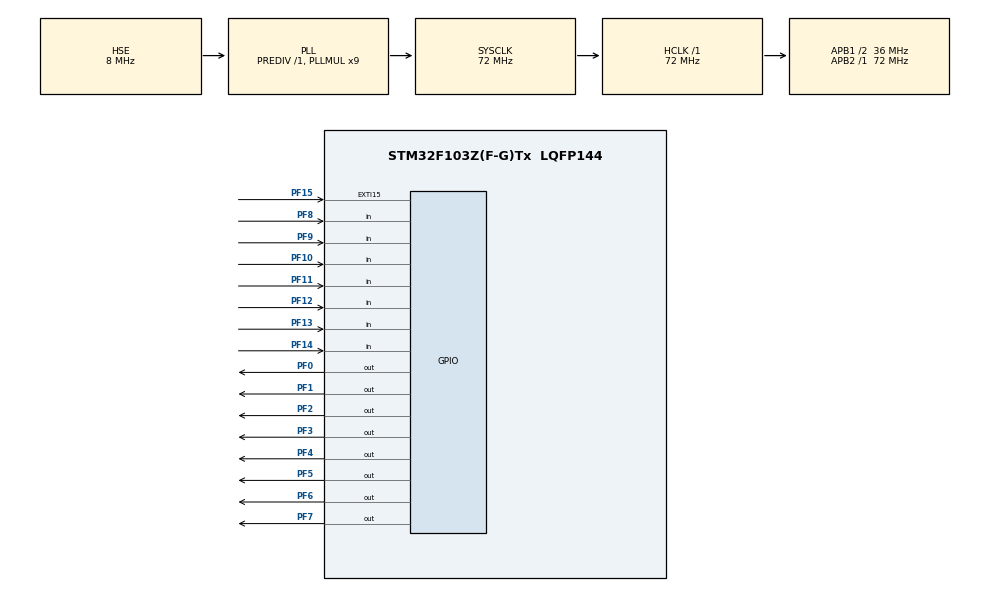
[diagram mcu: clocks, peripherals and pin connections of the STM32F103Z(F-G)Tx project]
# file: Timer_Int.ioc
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Mcu.Family=STM32F1
Mcu.Name=STM32F103Z(F-G)Tx
Mcu.Package=LQFP144
NVIC.EXTI15_10_IRQn=true\:0\:0\:false\:false\:true\:true\:true
NVIC.PriorityGroup=NVIC_PRIORITYGROUP_4
NVIC.TIM3_IRQn=true\:0\:0\:false\:false\:true\:true\:true
OSC_IN.Mode=HSE-External-Oscillator
OSC_IN.Signal=RCC_OSC_IN
OSC_OUT.Mode=HSE-External-Oscillator
OSC_OUT.Signal=RCC_OSC_OUT
PA13.Mode=Serial_Wire
PA13.Signal=SYS_JTMS-SWDIO
PA14.Mode=Serial_Wire
PA14.Signal=SYS_JTCK-SWCLK
PF0.Signal=GPIO_Output
PF1.Signal=GPIO_Output
PF10.Signal=GPIO_Input
PF11.Signal=GPIO_Input
PF12.Signal=GPIO_Input
PF13.Signal=GPIO_Input
PF14.Signal=GPIO_Input
PF15.GPIO_ModeDefaultEXTI=GPIO_MODE_IT_RISING
PF15.Signal=GPXTI15
PF2.Signal=GPIO_Output
PF3.Signal=GPIO_Output
PF4.Signal=GPIO_Output
PF5.Signal=GPIO_Output
PF6.Signal=GPIO_Output
PF7.Signal=GPIO_Output
PF8.Signal=GPIO_Input
PF9.Signal=GPIO_Input
ProjectManager.HeapSize=0x200
ProjectManager.StackSize=0x400
ProjectManager.TargetToolchain=MDK-ARM V5.27
RCC.AHBFreq_Value=72000000
RCC.APB1CLKDivider=RCC_HCLK_DIV2
RCC.APB1Freq_Value=36000000
RCC.APB1TimFreq_Value=72000000
RCC.APB2Freq_Value=72000000
RCC.APB2TimFreq_Value=72000000
RCC.HCLKFreq_Value=72000000
RCC.PLLMUL=RCC_PLL_MUL9
RCC.PLLSourceVirtual=RCC_PLLSOURCE_HSE
RCC.SYSCLKFreq_VALUE=72000000
RCC.SYSCLKSource=RCC_SYSCLKSOURCE_PLLCLK
RCC.USBFreq_Value=72000000
TIM3.AutoReloadPreload=TIM_AUTORELOAD_PRELOAD_DISABLE
VP_TIM3_VS_ClockSourceINT.Mode=Internal
board=custom

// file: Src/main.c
/* USER CODE BEGIN Header */
/**
  ******************************************************************************
  * @file           : main.c
  * @brief          : Main program body
  ******************************************************************************
  * @attention
  *
  * <h2><center>&copy; Copyright (c) 2021 STMicroelectronics.
  * All rights reserved.</center></h2>
  *
  * This software component is licensed by ST under BSD 3-Clause license,
  * the "License"; You may not use this file except in compliance with the
  * License. You may obtain a copy of the License at:
  *                        opensource.org/licenses/BSD-3-Clause
  *
  ******************************************************************************
  */
/* USER CODE END Header */
#include "main.h"

TIM_HandleTypeDef htim3;

void SystemClock_Config(void);
static void MX_GPIO_Init(void);
static void MX_TIM3_Init(void);

int main(void)
{

  HAL_Init();

  /* Configure the system clock */
  SystemClock_Config();

  /* Initialize all configured peripherals */
  MX_GPIO_Init();
  MX_TIM3_Init();
  /* USER CODE BEGIN 2 */

  HAL_GPIO_WritePin(GPIOA, GPIO_PIN_0, GPIO_PIN_RESET);
	HAL_GPIO_WritePin(GPIOA, GPIO_PIN_1, GPIO_PIN_RESET);
	HAL_GPIO_WritePin(GPIOA, GPIO_PIN_2, GPIO_PIN_RESET);

	HAL_GPIO_WritePin(GPIOF, GPIO_PIN_1, GPIO_PIN_SET);

	HAL_TIM_Base_Start_IT(&htim3);

  while (1)
  {
       //HAL_Delay(1000);
  }

}

void SystemClock_Config(void)
{
  RCC_OscInitTypeDef RCC_OscInitStruct = {0};
  RCC_ClkInitTypeDef RCC_ClkInitStruct = {0};

  /** Initializes the RCC Oscillators according to the specified parameters
  * in the RCC_OscInitTypeDef structure.
  */
  RCC_OscInitStruct.OscillatorType = RCC_OSCILLATORTYPE_HSE;
  RCC_OscInitStruct.HSEState = RCC_HSE_ON;
  RCC_OscInitStruct.HSEPredivValue = RCC_HSE_PREDIV_DIV1;
  RCC_OscInitStruct.HSIState = RCC_HSI_ON;
  RCC_OscInitStruct.PLL.PLLState = RCC_PLL_ON;
  RCC_OscInitStruct.PLL.PLLSource = RCC_PLLSOURCE_HSE;
  RCC_OscInitStruct.PLL.PLLMUL = RCC_PLL_MUL9;
  if (HAL_RCC_OscConfig(&RCC_OscInitStruct) != HAL_OK)
  {
    Error_Handler();
  }
  /** Initializes the CPU, AHB and APB buses clocks
  */
  RCC_ClkInitStruct.ClockType = RCC_CLOCKTYPE_HCLK|RCC_CLOCKTYPE_SYSCLK
                              |RCC_CLOCKTYPE_PCLK1|RCC_CLOCKTYPE_PCLK2;
  RCC_ClkInitStruct.SYSCLKSource = RCC_SYSCLKSOURCE_PLLCLK;
  RCC_ClkInitStruct.AHBCLKDivider = RCC_SYSCLK_DIV1;
  RCC_ClkInitStruct.APB1CLKDivider = RCC_HCLK_DIV2;
  RCC_ClkInitStruct.APB2CLKDivider = RCC_HCLK_DIV1;

  if (HAL_RCC_ClockConfig(&RCC_ClkInitStruct, FLASH_LATENCY_2) != HAL_OK)
  {
    Error_Handler();
  }
}

static void MX_TIM3_Init(void)
{

  TIM_ClockConfigTypeDef sClockSourceConfig = {0};
  TIM_MasterConfigTypeDef sMasterConfig = {0};

  htim3.Instance = TIM3;
  htim3.Init.Prescaler = 719;
  htim3.Init.CounterMode = TIM_COUNTERMODE_UP;
  htim3.Init.Period = 50000;
  htim3.Init.ClockDivision = TIM_CLOCKDIVISION_DIV1;
  htim3.Init.AutoReloadPreload = TIM_AUTORELOAD_PRELOAD_DISABLE;
  if (HAL_TIM_Base_Init(&htim3) != HAL_OK)
  {
    Error_Handler();
  }
  sClockSourceConfig.ClockSource = TIM_CLOCKSOURCE_INTERNAL;
  if (HAL_TIM_ConfigClockSource(&htim3, &sClockSourceConfig) != HAL_OK)
  {
    Error_Handler();
  }
  sMasterConfig.MasterOutputTrigger = TIM_TRGO_RESET;
  sMasterConfig.MasterSlaveMode = TIM_MASTERSLAVEMODE_DISABLE;
  if (HAL_TIMEx_MasterConfigSynchronization(&htim3, &sMasterConfig) != HAL_OK)
  {
    Error_Handler();
  }

}

static void MX_GPIO_Init(void)
{
  GPIO_InitTypeDef GPIO_InitStruct = {0};

  /* GPIO Ports Clock Enable */
  __HAL_RCC_GPIOF_CLK_ENABLE();
  __HAL_RCC_GPIOA_CLK_ENABLE();

  /*Configure GPIO pin Output Level */
  HAL_GPIO_WritePin(GPIOF, GPIO_PIN_0|GPIO_PIN_1|GPIO_PIN_2|GPIO_PIN_3
                          |GPIO_PIN_4|GPIO_PIN_5|GPIO_PIN_6|GPIO_PIN_7, GPIO_PIN_RESET);

  /*Configure GPIO pins : PF0 PF1 PF2 PF3
                           PF4 PF5 PF6 PF7 */
  GPIO_InitStruct.Pin = GPIO_PIN_0|GPIO_PIN_1|GPIO_PIN_2|GPIO_PIN_3
                          |GPIO_PIN_4|GPIO_PIN_5|GPIO_PIN_6|GPIO_PIN_7;
  GPIO_InitStruct.Mode = GPIO_MODE_OUTPUT_PP;
  GPIO_InitStruct.Pull = GPIO_NOPULL;
  GPIO_InitStruct.Speed = GPIO_SPEED_FREQ_LOW;
  HAL_GPIO_Init(GPIOF, &GPIO_InitStruct);

  /*Configure GPIO pins : PF8 PF9 PF10 PF11
                           PF12 PF13 PF14 */
  GPIO_InitStruct.Pin = GPIO_PIN_8|GPIO_PIN_9|GPIO_PIN_10|GPIO_PIN_11
                          |GPIO_PIN_12|GPIO_PIN_13|GPIO_PIN_14;
  GPIO_InitStruct.Mode = GPIO_MODE_INPUT;
  GPIO_InitStruct.Pull = GPIO_NOPULL;
  HAL_GPIO_Init(GPIOF, &GPIO_InitStruct);

  GPIO_InitStruct.Pin = GPIO_PIN_0|GPIO_PIN_1|GPIO_PIN_2;
  GPIO_InitStruct.Mode = GPIO_MODE_OUTPUT_PP;
  GPIO_InitStruct.Pull = GPIO_NOPULL;
  HAL_GPIO_Init(GPIOA, &GPIO_InitStruct);

  /*Configure GPIO pin : PF15 */
  GPIO_InitStruct.Pin = GPIO_PIN_15;
  GPIO_InitStruct.Mode = GPIO_MODE_IT_FALLING;
  GPIO_InitStruct.Pull = GPIO_NOPULL;
  HAL_GPIO_Init(GPIOF, &GPIO_InitStruct);

  /* EXTI interrupt init*/
  HAL_NVIC_SetPriority(EXTI15_10_IRQn, 0, 0);
  HAL_NVIC_EnableIRQ(EXTI15_10_IRQn);

}

/* USER CODE BEGIN 4 */
void HAL_TIM_PeriodElapsedCallback(TIM_HandleTypeDef *htim)
{
    if(htim->Instance == TIM3)
    {
          HAL_GPIO_TogglePin(GPIOF, GPIO_PIN_1);
    }
}

void HAL_GPIO_EXTI_Callback(uint16_t GPIO_Pin)
{
  if(GPIO_Pin == GPIO_PIN_15)
  {
         HAL_GPIO_TogglePin(GPIOF, GPIO_PIN_2);
  }

}
void Error_Handler(void)
{

}

/************************ (C) COPYRIGHT STMicroelectronics *****END OF FILE****/
